VERSION 5.7 ;
  NOWIREEXTENSIONATPIN ON ;
  DIVIDERCHAR "/" ;
  BUSBITCHARS "[]" ;
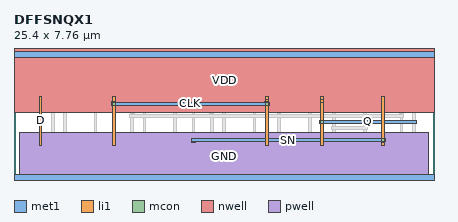
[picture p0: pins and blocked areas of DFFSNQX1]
MACRO DFFSNQX1
  CLASS CORE ;
  FOREIGN DFFSNQX1 ;
  ORIGIN 0.000 0.000 ;
  SIZE 25.400 BY 7.760 ;
  SYMMETRY X Y ;
  SITE unitrh ;
  PIN Q
    DIRECTION OUTPUT ;
    USE SIGNAL ;
    ANTENNAGATEAREA 1.027250 ;
    ANTENNADIFFAREA 1.931900 ;
    PORT
      LAYER met1 ;
        RECT 18.505 3.595 18.735 3.625 ;
        RECT 24.055 3.595 24.285 3.625 ;
        RECT 18.475 3.425 24.315 3.595 ;
        RECT 18.505 3.395 18.735 3.425 ;
        RECT 24.055 3.395 24.285 3.425 ;
    END
    PORT
      LAYER li1 ;
        RECT 18.565 4.890 18.735 5.045 ;
        RECT 18.535 4.715 18.735 4.890 ;
        RECT 18.535 2.095 18.705 4.715 ;
      LAYER mcon ;
        RECT 18.535 3.425 18.705 3.595 ;
    END
  END Q
  PIN D
    DIRECTION INPUT ;
    USE SIGNAL ;
    ANTENNAGATEAREA 1.033250 ;
    PORT
      LAYER li1 ;
        RECT 1.515 2.095 1.685 5.045 ;
    END
  END D
  PIN CLK
    DIRECTION INPUT ;
    USE SIGNAL ;
    ANTENNAGATEAREA 2.042100 ;
    PORT
      LAYER met1 ;
        RECT 5.925 4.705 6.155 4.735 ;
        RECT 15.175 4.705 15.405 4.735 ;
        RECT 5.895 4.535 15.435 4.705 ;
        RECT 5.925 4.505 6.155 4.535 ;
        RECT 15.175 4.505 15.405 4.535 ;
    END
    PORT
      LAYER li1 ;
        RECT 5.955 2.095 6.125 5.045 ;
      LAYER mcon ;
        RECT 5.955 4.535 6.125 4.705 ;
    END
    PORT
      LAYER li1 ;
        RECT 15.235 4.890 15.405 5.045 ;
        RECT 15.205 4.715 15.405 4.890 ;
        RECT 15.205 2.095 15.375 4.715 ;
      LAYER mcon ;
        RECT 15.205 4.535 15.375 4.705 ;
    END
  END CLK
  PIN SN
    DIRECTION INPUT ;
    USE SIGNAL ;
    ANTENNAGATEAREA 2.029700 ;
    PORT
      LAYER met1 ;
        RECT 10.735 2.485 10.965 2.515 ;
        RECT 22.205 2.485 22.435 2.515 ;
        RECT 10.705 2.315 22.465 2.485 ;
        RECT 10.735 2.285 10.965 2.315 ;
        RECT 22.205 2.285 22.435 2.315 ;
    END
    PORT
      LAYER li1 ;
        RECT 22.235 2.095 22.405 5.045 ;
      LAYER mcon ;
        RECT 22.235 2.315 22.405 2.485 ;
    END
  END SN
  PIN VDD
    DIRECTION INOUT ;
    USE POWER ;
    SHAPE ABUTMENT ;
    PORT
      LAYER nwell ;
        RECT 0.000 4.110 25.400 7.940 ;
      LAYER met1 ;
        RECT 0.000 7.410 25.400 7.760 ;
    END
  END VDD
  PIN GND
    DIRECTION INOUT ;
    USE GROUND ;
    SHAPE ABUTMENT ;
    PORT
      LAYER pwell ;
        RECT 0.320 0.000 25.080 2.900 ;
      LAYER met1 ;
        RECT 0.000 0.000 25.400 0.350 ;
    END
  END GND
  OBS
      LAYER li1 ;
        RECT 0.000 7.410 25.400 7.760 ;
        RECT 0.320 4.290 0.660 7.410 ;
        RECT 1.195 5.315 1.365 7.410 ;
        RECT 1.635 5.465 1.805 7.200 ;
        RECT 2.075 5.735 2.245 7.410 ;
        RECT 2.515 5.465 2.685 7.200 ;
        RECT 2.955 5.735 3.125 7.410 ;
        RECT 1.635 5.295 3.165 5.465 ;
        RECT 2.285 4.890 2.455 5.045 ;
        RECT 2.255 4.715 2.455 4.890 ;
        RECT 0.320 0.350 0.660 2.900 ;
        RECT 2.255 2.095 2.425 4.715 ;
        RECT 1.100 1.845 1.270 1.925 ;
        RECT 2.070 1.845 2.240 1.925 ;
        RECT 2.995 1.920 3.165 5.295 ;
        RECT 3.650 4.290 3.990 7.410 ;
        RECT 4.825 5.395 4.995 7.410 ;
        RECT 5.265 5.420 5.435 7.200 ;
        RECT 5.705 5.735 5.875 7.410 ;
        RECT 6.145 5.420 6.315 7.200 ;
        RECT 6.585 5.735 6.755 7.410 ;
        RECT 7.025 5.420 7.195 7.200 ;
        RECT 7.465 5.735 7.635 7.410 ;
        RECT 5.265 5.250 7.975 5.420 ;
        RECT 1.100 1.675 2.240 1.845 ;
        RECT 1.100 0.545 1.270 1.675 ;
        RECT 1.585 0.350 1.755 1.300 ;
        RECT 2.070 0.795 2.240 1.675 ;
        RECT 2.555 1.750 3.165 1.920 ;
        RECT 2.555 1.015 2.725 1.750 ;
        RECT 3.040 0.795 3.210 1.565 ;
        RECT 2.070 0.625 3.210 0.795 ;
        RECT 2.070 0.545 2.240 0.625 ;
        RECT 3.040 0.545 3.210 0.625 ;
        RECT 3.650 0.350 3.990 2.900 ;
        RECT 4.845 2.095 5.015 5.045 ;
        RECT 7.065 2.095 7.235 5.045 ;
        RECT 7.805 4.415 7.975 5.250 ;
        RECT 7.800 4.085 7.975 4.415 ;
        RECT 8.460 4.290 8.800 7.410 ;
        RECT 9.635 5.395 9.805 7.410 ;
        RECT 10.075 5.420 10.245 7.200 ;
        RECT 10.515 5.735 10.685 7.410 ;
        RECT 10.955 5.420 11.125 7.200 ;
        RECT 11.395 5.735 11.565 7.410 ;
        RECT 11.835 5.420 12.005 7.200 ;
        RECT 12.275 5.735 12.445 7.410 ;
        RECT 10.075 5.250 12.785 5.420 ;
        RECT 4.325 1.855 4.495 1.935 ;
        RECT 5.295 1.855 5.465 1.935 ;
        RECT 6.265 1.855 6.435 1.935 ;
        RECT 4.325 1.685 6.435 1.855 ;
        RECT 4.325 0.555 4.495 1.685 ;
        RECT 4.810 0.350 4.980 1.310 ;
        RECT 5.295 0.805 5.465 1.685 ;
        RECT 6.265 1.605 6.435 1.685 ;
        RECT 5.785 1.260 5.955 1.340 ;
        RECT 6.835 1.260 7.005 1.935 ;
        RECT 7.805 1.930 7.975 4.085 ;
        RECT 5.785 1.090 7.005 1.260 ;
        RECT 5.785 1.010 5.955 1.090 ;
        RECT 6.265 0.805 6.435 0.885 ;
        RECT 5.295 0.635 6.435 0.805 ;
        RECT 5.295 0.555 5.465 0.635 ;
        RECT 6.265 0.555 6.435 0.635 ;
        RECT 6.835 0.805 7.005 1.090 ;
        RECT 7.320 1.760 7.975 1.930 ;
        RECT 7.320 1.025 7.490 1.760 ;
        RECT 7.805 0.805 7.975 1.575 ;
        RECT 6.835 0.635 7.975 0.805 ;
        RECT 6.835 0.555 7.005 0.635 ;
        RECT 7.805 0.555 7.975 0.635 ;
        RECT 8.460 0.350 8.800 2.900 ;
        RECT 9.655 2.095 9.825 5.045 ;
        RECT 10.765 2.095 10.935 5.045 ;
        RECT 11.875 2.095 12.045 5.045 ;
        RECT 9.135 1.855 9.305 1.935 ;
        RECT 10.105 1.855 10.275 1.935 ;
        RECT 11.075 1.855 11.245 1.935 ;
        RECT 9.135 1.685 11.245 1.855 ;
        RECT 9.135 0.555 9.305 1.685 ;
        RECT 9.620 0.350 9.790 1.310 ;
        RECT 10.105 0.805 10.275 1.685 ;
        RECT 11.075 1.605 11.245 1.685 ;
        RECT 10.595 1.260 10.765 1.340 ;
        RECT 11.645 1.260 11.815 1.935 ;
        RECT 12.615 1.930 12.785 5.250 ;
        RECT 13.270 4.290 13.610 7.410 ;
        RECT 14.145 5.315 14.315 7.410 ;
        RECT 14.585 5.465 14.755 7.200 ;
        RECT 15.025 5.735 15.195 7.410 ;
        RECT 15.465 5.465 15.635 7.200 ;
        RECT 15.905 5.735 16.075 7.410 ;
        RECT 14.585 5.295 16.115 5.465 ;
        RECT 10.595 1.090 11.815 1.260 ;
        RECT 10.595 1.010 10.765 1.090 ;
        RECT 11.075 0.805 11.245 0.885 ;
        RECT 10.105 0.635 11.245 0.805 ;
        RECT 10.105 0.555 10.275 0.635 ;
        RECT 11.075 0.555 11.245 0.635 ;
        RECT 11.645 0.805 11.815 1.090 ;
        RECT 12.130 1.760 12.785 1.930 ;
        RECT 12.130 1.025 12.300 1.760 ;
        RECT 12.615 0.805 12.785 1.575 ;
        RECT 11.645 0.635 12.785 0.805 ;
        RECT 11.645 0.555 11.815 0.635 ;
        RECT 12.615 0.555 12.785 0.635 ;
        RECT 13.270 0.350 13.610 2.900 ;
        RECT 14.465 2.095 14.635 5.045 ;
        RECT 14.050 1.845 14.220 1.925 ;
        RECT 15.020 1.845 15.190 1.925 ;
        RECT 15.945 1.920 16.115 5.295 ;
        RECT 16.600 4.290 16.940 7.410 ;
        RECT 17.475 5.315 17.645 7.410 ;
        RECT 17.915 5.465 18.085 7.200 ;
        RECT 18.355 5.735 18.525 7.410 ;
        RECT 18.795 5.465 18.965 7.200 ;
        RECT 19.235 5.735 19.405 7.410 ;
        RECT 17.915 5.295 19.445 5.465 ;
        RECT 14.050 1.675 15.190 1.845 ;
        RECT 14.050 0.545 14.220 1.675 ;
        RECT 14.535 0.350 14.705 1.300 ;
        RECT 15.020 0.795 15.190 1.675 ;
        RECT 15.505 1.750 16.115 1.920 ;
        RECT 15.505 1.015 15.675 1.750 ;
        RECT 15.990 0.795 16.160 1.565 ;
        RECT 15.020 0.625 16.160 0.795 ;
        RECT 15.020 0.545 15.190 0.625 ;
        RECT 15.990 0.545 16.160 0.625 ;
        RECT 16.600 0.350 16.940 2.900 ;
        RECT 17.795 2.095 17.965 5.045 ;
        RECT 17.380 1.845 17.550 1.925 ;
        RECT 18.350 1.845 18.520 1.925 ;
        RECT 19.275 1.920 19.445 5.295 ;
        RECT 19.930 4.290 20.270 7.410 ;
        RECT 21.105 5.395 21.275 7.410 ;
        RECT 21.545 5.420 21.715 7.200 ;
        RECT 21.985 5.735 22.155 7.410 ;
        RECT 22.425 5.420 22.595 7.200 ;
        RECT 22.865 5.735 23.035 7.410 ;
        RECT 23.305 5.420 23.475 7.200 ;
        RECT 23.745 5.735 23.915 7.410 ;
        RECT 21.545 5.250 24.255 5.420 ;
        RECT 17.380 1.675 18.520 1.845 ;
        RECT 17.380 0.545 17.550 1.675 ;
        RECT 17.865 0.350 18.035 1.300 ;
        RECT 18.350 0.795 18.520 1.675 ;
        RECT 18.835 1.750 19.445 1.920 ;
        RECT 18.835 1.015 19.005 1.750 ;
        RECT 19.320 0.795 19.490 1.565 ;
        RECT 18.350 0.625 19.490 0.795 ;
        RECT 18.350 0.545 18.520 0.625 ;
        RECT 19.320 0.545 19.490 0.625 ;
        RECT 19.930 0.350 20.270 2.900 ;
        RECT 21.125 2.095 21.295 5.045 ;
        RECT 23.345 2.095 23.515 5.045 ;
        RECT 20.605 1.855 20.775 1.935 ;
        RECT 21.575 1.855 21.745 1.935 ;
        RECT 22.545 1.855 22.715 1.935 ;
        RECT 20.605 1.685 22.715 1.855 ;
        RECT 20.605 0.555 20.775 1.685 ;
        RECT 21.090 0.350 21.260 1.310 ;
        RECT 21.575 0.805 21.745 1.685 ;
        RECT 22.545 1.605 22.715 1.685 ;
        RECT 22.065 1.260 22.235 1.340 ;
        RECT 23.115 1.260 23.285 1.935 ;
        RECT 24.085 1.930 24.255 5.250 ;
        RECT 24.740 4.290 25.080 7.410 ;
        RECT 22.065 1.090 23.285 1.260 ;
        RECT 22.065 1.010 22.235 1.090 ;
        RECT 22.545 0.805 22.715 0.885 ;
        RECT 21.575 0.635 22.715 0.805 ;
        RECT 21.575 0.555 21.745 0.635 ;
        RECT 22.545 0.555 22.715 0.635 ;
        RECT 23.115 0.805 23.285 1.090 ;
        RECT 23.600 1.760 24.255 1.930 ;
        RECT 23.600 1.025 23.770 1.760 ;
        RECT 24.085 0.805 24.255 1.575 ;
        RECT 23.115 0.635 24.255 0.805 ;
        RECT 23.115 0.555 23.285 0.635 ;
        RECT 24.085 0.555 24.255 0.635 ;
        RECT 24.740 0.350 25.080 2.900 ;
        RECT 0.000 0.000 25.400 0.350 ;
      LAYER mcon ;
        RECT 0.775 7.495 0.945 7.665 ;
        RECT 1.145 7.495 1.315 7.665 ;
        RECT 1.515 7.495 1.685 7.665 ;
        RECT 1.885 7.495 2.055 7.665 ;
        RECT 2.255 7.495 2.425 7.665 ;
        RECT 2.625 7.495 2.795 7.665 ;
        RECT 2.995 7.495 3.165 7.665 ;
        RECT 3.365 7.495 3.535 7.665 ;
        RECT 4.105 7.495 4.275 7.665 ;
        RECT 4.475 7.495 4.645 7.665 ;
        RECT 4.845 7.495 5.015 7.665 ;
        RECT 5.215 7.495 5.385 7.665 ;
        RECT 5.585 7.495 5.755 7.665 ;
        RECT 5.955 7.495 6.125 7.665 ;
        RECT 6.325 7.495 6.495 7.665 ;
        RECT 6.695 7.495 6.865 7.665 ;
        RECT 7.065 7.495 7.235 7.665 ;
        RECT 7.435 7.495 7.605 7.665 ;
        RECT 7.805 7.495 7.975 7.665 ;
        RECT 8.175 7.495 8.345 7.665 ;
        RECT 8.915 7.495 9.085 7.665 ;
        RECT 9.285 7.495 9.455 7.665 ;
        RECT 9.655 7.495 9.825 7.665 ;
        RECT 10.025 7.495 10.195 7.665 ;
        RECT 10.395 7.495 10.565 7.665 ;
        RECT 10.765 7.495 10.935 7.665 ;
        RECT 11.135 7.495 11.305 7.665 ;
        RECT 11.505 7.495 11.675 7.665 ;
        RECT 11.875 7.495 12.045 7.665 ;
        RECT 12.245 7.495 12.415 7.665 ;
        RECT 12.615 7.495 12.785 7.665 ;
        RECT 12.985 7.495 13.155 7.665 ;
        RECT 13.725 7.495 13.895 7.665 ;
        RECT 14.095 7.495 14.265 7.665 ;
        RECT 14.465 7.495 14.635 7.665 ;
        RECT 14.835 7.495 15.005 7.665 ;
        RECT 15.205 7.495 15.375 7.665 ;
        RECT 15.575 7.495 15.745 7.665 ;
        RECT 15.945 7.495 16.115 7.665 ;
        RECT 16.315 7.495 16.485 7.665 ;
        RECT 17.055 7.495 17.225 7.665 ;
        RECT 17.425 7.495 17.595 7.665 ;
        RECT 17.795 7.495 17.965 7.665 ;
        RECT 18.165 7.495 18.335 7.665 ;
        RECT 18.535 7.495 18.705 7.665 ;
        RECT 18.905 7.495 19.075 7.665 ;
        RECT 19.275 7.495 19.445 7.665 ;
        RECT 19.645 7.495 19.815 7.665 ;
        RECT 20.385 7.495 20.555 7.665 ;
        RECT 20.755 7.495 20.925 7.665 ;
        RECT 21.125 7.495 21.295 7.665 ;
        RECT 21.495 7.495 21.665 7.665 ;
        RECT 21.865 7.495 22.035 7.665 ;
        RECT 22.235 7.495 22.405 7.665 ;
        RECT 22.605 7.495 22.775 7.665 ;
        RECT 22.975 7.495 23.145 7.665 ;
        RECT 23.345 7.495 23.515 7.665 ;
        RECT 23.715 7.495 23.885 7.665 ;
        RECT 24.085 7.495 24.255 7.665 ;
        RECT 24.455 7.495 24.625 7.665 ;
        RECT 2.255 4.165 2.425 4.335 ;
        RECT 2.995 2.685 3.165 2.855 ;
        RECT 4.845 2.680 5.015 2.850 ;
        RECT 7.800 4.165 7.970 4.335 ;
        RECT 7.065 3.795 7.235 3.965 ;
        RECT 9.655 2.685 9.825 2.855 ;
        RECT 10.765 2.315 10.935 2.485 ;
        RECT 11.875 3.795 12.045 3.965 ;
        RECT 12.615 2.685 12.785 2.855 ;
        RECT 14.465 2.685 14.635 2.855 ;
        RECT 15.945 3.795 16.115 3.965 ;
        RECT 17.795 4.165 17.965 4.335 ;
        RECT 19.275 3.055 19.445 3.225 ;
        RECT 21.125 3.055 21.295 3.225 ;
        RECT 23.345 3.795 23.515 3.965 ;
        RECT 24.085 3.425 24.255 3.595 ;
        RECT 0.775 0.095 0.945 0.265 ;
        RECT 1.145 0.095 1.315 0.265 ;
        RECT 1.515 0.095 1.685 0.265 ;
        RECT 1.885 0.095 2.055 0.265 ;
        RECT 2.255 0.095 2.425 0.265 ;
        RECT 2.625 0.095 2.795 0.265 ;
        RECT 2.995 0.095 3.165 0.265 ;
        RECT 3.365 0.095 3.535 0.265 ;
        RECT 4.105 0.095 4.275 0.265 ;
        RECT 4.475 0.095 4.645 0.265 ;
        RECT 4.845 0.095 5.015 0.265 ;
        RECT 5.215 0.095 5.385 0.265 ;
        RECT 5.585 0.095 5.755 0.265 ;
        RECT 5.955 0.095 6.125 0.265 ;
        RECT 6.325 0.095 6.495 0.265 ;
        RECT 6.695 0.095 6.865 0.265 ;
        RECT 7.065 0.095 7.235 0.265 ;
        RECT 7.435 0.095 7.605 0.265 ;
        RECT 7.805 0.095 7.975 0.265 ;
        RECT 8.175 0.095 8.345 0.265 ;
        RECT 8.915 0.095 9.085 0.265 ;
        RECT 9.285 0.095 9.455 0.265 ;
        RECT 9.655 0.095 9.825 0.265 ;
        RECT 10.025 0.095 10.195 0.265 ;
        RECT 10.395 0.095 10.565 0.265 ;
        RECT 10.765 0.095 10.935 0.265 ;
        RECT 11.135 0.095 11.305 0.265 ;
        RECT 11.505 0.095 11.675 0.265 ;
        RECT 11.875 0.095 12.045 0.265 ;
        RECT 12.245 0.095 12.415 0.265 ;
        RECT 12.615 0.095 12.785 0.265 ;
        RECT 12.985 0.095 13.155 0.265 ;
        RECT 13.725 0.095 13.895 0.265 ;
        RECT 14.095 0.095 14.265 0.265 ;
        RECT 14.465 0.095 14.635 0.265 ;
        RECT 14.835 0.095 15.005 0.265 ;
        RECT 15.205 0.095 15.375 0.265 ;
        RECT 15.575 0.095 15.745 0.265 ;
        RECT 15.945 0.095 16.115 0.265 ;
        RECT 16.315 0.095 16.485 0.265 ;
        RECT 17.055 0.095 17.225 0.265 ;
        RECT 17.425 0.095 17.595 0.265 ;
        RECT 17.795 0.095 17.965 0.265 ;
        RECT 18.165 0.095 18.335 0.265 ;
        RECT 18.535 0.095 18.705 0.265 ;
        RECT 18.905 0.095 19.075 0.265 ;
        RECT 19.275 0.095 19.445 0.265 ;
        RECT 19.645 0.095 19.815 0.265 ;
        RECT 20.385 0.095 20.555 0.265 ;
        RECT 20.755 0.095 20.925 0.265 ;
        RECT 21.125 0.095 21.295 0.265 ;
        RECT 21.495 0.095 21.665 0.265 ;
        RECT 21.865 0.095 22.035 0.265 ;
        RECT 22.235 0.095 22.405 0.265 ;
        RECT 22.605 0.095 22.775 0.265 ;
        RECT 22.975 0.095 23.145 0.265 ;
        RECT 23.345 0.095 23.515 0.265 ;
        RECT 23.715 0.095 23.885 0.265 ;
        RECT 24.085 0.095 24.255 0.265 ;
        RECT 24.455 0.095 24.625 0.265 ;
      LAYER met1 ;
        RECT 2.225 4.335 2.455 4.365 ;
        RECT 7.770 4.335 8.000 4.365 ;
        RECT 17.765 4.335 17.995 4.365 ;
        RECT 2.195 4.165 18.025 4.335 ;
        RECT 2.225 4.135 2.455 4.165 ;
        RECT 7.770 4.135 8.000 4.165 ;
        RECT 17.765 4.135 17.995 4.165 ;
        RECT 7.035 3.965 7.265 3.995 ;
        RECT 11.845 3.965 12.075 3.995 ;
        RECT 15.915 3.965 16.145 3.995 ;
        RECT 23.315 3.965 23.545 3.995 ;
        RECT 7.005 3.795 23.575 3.965 ;
        RECT 7.035 3.765 7.265 3.795 ;
        RECT 11.845 3.765 12.075 3.795 ;
        RECT 15.915 3.765 16.145 3.795 ;
        RECT 23.315 3.765 23.545 3.795 ;
        RECT 19.245 3.225 19.475 3.255 ;
        RECT 21.095 3.225 21.325 3.255 ;
        RECT 19.215 3.055 21.355 3.225 ;
        RECT 19.245 3.025 19.475 3.055 ;
        RECT 21.095 3.025 21.325 3.055 ;
        RECT 2.965 2.855 3.195 2.885 ;
        RECT 4.815 2.855 5.045 2.880 ;
        RECT 9.625 2.855 9.855 2.885 ;
        RECT 12.585 2.855 12.815 2.885 ;
        RECT 14.435 2.855 14.665 2.885 ;
        RECT 2.935 2.685 9.885 2.855 ;
        RECT 12.555 2.685 14.695 2.855 ;
        RECT 2.965 2.655 3.195 2.685 ;
        RECT 4.785 2.680 5.195 2.685 ;
        RECT 4.815 2.650 5.045 2.680 ;
        RECT 9.625 2.655 9.855 2.685 ;
        RECT 12.585 2.655 12.815 2.685 ;
        RECT 14.435 2.655 14.665 2.685 ;
  END
END DFFSNQX1
END LIBRARY

